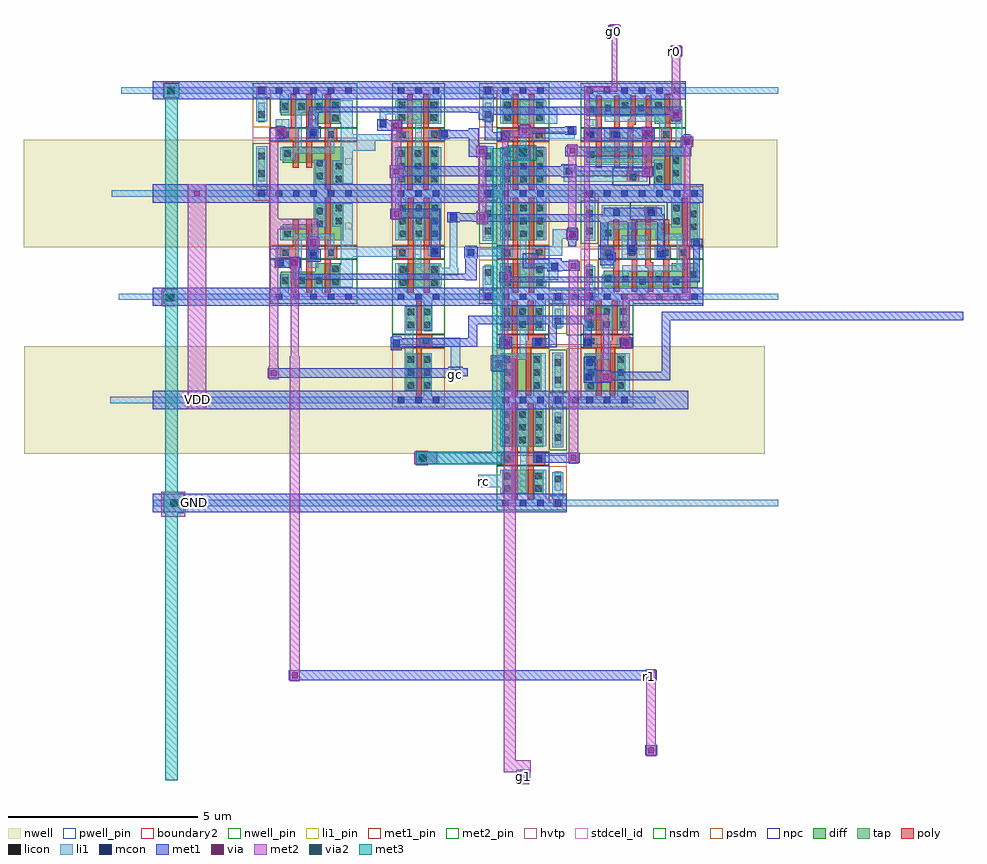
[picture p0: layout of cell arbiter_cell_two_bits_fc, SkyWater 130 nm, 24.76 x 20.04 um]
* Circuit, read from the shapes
.subckt arbiter_cell_two_bits_fc GND VDD g0 g1 gc r0 r1 rc
XM1 n1 r1 GND GND sky130_fd_pr__nfet_01v8 w=0.42 l=0.15
XM2 n2 gc GND GND sky130_fd_pr__nfet_01v8 w=0.42 l=0.15
XM3 GND gc n1 GND sky130_fd_pr__nfet_01v8 w=0.42 l=0.15
XM4 GND r0 n2 GND sky130_fd_pr__nfet_01v8 w=0.42 l=0.15
XM5 sky130_fd_sc_hd__nand2_1_8/B n1 GND GND sky130_fd_pr__nfet_01v8 w=0.65 l=0.15
XM6 sky130_fd_sc_hd__nand2_1_15/A n2 GND GND sky130_fd_pr__nfet_01v8 w=0.65 l=0.15
XM7 n3 sky130_fd_sc_hd__nand2_1_15/A sky130_fd_sc_hd__nand2_1_8/A GND sky130_fd_pr__nfet_01v8 w=0.65 l=0.15
XM8 n4 sky130_fd_sc_hd__nand2_1_8/B GND GND sky130_fd_pr__nfet_01v8 w=0.65 l=0.15
XM9 GND gc sky130_fd_sc_hd__nor2_1_3/A GND sky130_fd_pr__nfet_01v8 w=0.65 l=0.15
XM10 GND sky130_fd_sc_hd__or4_1_11/A n3 GND sky130_fd_pr__nfet_01v8 w=0.65 l=0.15
XM11 sky130_fd_sc_hd__or4_1_11/A sky130_fd_sc_hd__nand2_1_8/A n4 GND sky130_fd_pr__nfet_01v8 w=0.65 l=0.15
XM12 n5 sky130_fd_sc_hd__nand2_1_2/A rc GND sky130_fd_pr__nfet_01v8 w=0.65 l=0.15
XM13 g1 sky130_fd_sc_hd__nand2_1_17/A GND GND sky130_fd_pr__nfet_01v8 w=0.65 l=0.15
XM14 n6 r1 GND GND sky130_fd_pr__nfet_01v8 w=0.65 l=0.15
XM15 n7 r0 GND GND sky130_fd_pr__nfet_01v8 w=0.65 l=0.15
XM16 GND sky130_fd_sc_hd__nand2_1_2/B n5 GND sky130_fd_pr__nfet_01v8 w=0.65 l=0.15
XM17 GND sky130_fd_sc_hd__nor2_1_3/A g1 GND sky130_fd_pr__nfet_01v8 w=0.65 l=0.15
XM18 sky130_fd_sc_hd__nand2_1_2/B sky130_fd_sc_hd__nand2_1_10/A n6 GND sky130_fd_pr__nfet_01v8 w=0.65 l=0.15
XM19 sky130_fd_sc_hd__nand2_1_2/A sky130_fd_sc_hd__nand2_1_17/A n7 GND sky130_fd_pr__nfet_01v8 w=0.65 l=0.15
XM20 g0 sky130_fd_sc_hd__nor2_1_3/A GND GND sky130_fd_pr__nfet_01v8 w=0.65 l=0.15
XM21 n8 sky130_fd_sc_hd__nand2_1_8/A GND GND sky130_fd_pr__nfet_01v8 w=0.42 l=0.15 m=4
XM22 GND sky130_fd_sc_hd__nand2_1_10/A g0 GND sky130_fd_pr__nfet_01v8 w=0.65 l=0.15
XM23 n9 sky130_fd_sc_hd__or4_1_11/A GND GND sky130_fd_pr__nfet_01v8 w=0.42 l=0.15 m=4
XM24 sky130_fd_sc_hd__nand2_1_10/A n8 GND GND sky130_fd_pr__nfet_01v8 w=0.65 l=0.15
XM25 sky130_fd_sc_hd__nand2_1_17/A n9 GND GND sky130_fd_pr__nfet_01v8 w=0.65 l=0.15
XM26 n10 r1 n1 VDD sky130_fd_pr__pfet_01v8_hvt w=0.42 l=0.15
XM27 n11 gc n2 VDD sky130_fd_pr__pfet_01v8_hvt w=0.42 l=0.15
XM28 VDD gc n10 VDD sky130_fd_pr__pfet_01v8_hvt w=0.42 l=0.15
XM29 VDD r0 n11 VDD sky130_fd_pr__pfet_01v8_hvt w=0.42 l=0.15
XM30 sky130_fd_sc_hd__nand2_1_8/B n1 VDD VDD sky130_fd_pr__pfet_01v8_hvt w=1 l=0.15
XM31 sky130_fd_sc_hd__nand2_1_15/A n2 VDD VDD sky130_fd_pr__pfet_01v8_hvt w=1 l=0.15
XM32 sky130_fd_sc_hd__nand2_1_8/A sky130_fd_sc_hd__nand2_1_15/A VDD VDD sky130_fd_pr__pfet_01v8_hvt w=1 l=0.15
XM33 sky130_fd_sc_hd__or4_1_11/A sky130_fd_sc_hd__nand2_1_8/B VDD VDD sky130_fd_pr__pfet_01v8_hvt w=1 l=0.15
XM34 VDD gc sky130_fd_sc_hd__nor2_1_3/A VDD sky130_fd_pr__pfet_01v8_hvt w=1 l=0.15
XM35 VDD sky130_fd_sc_hd__or4_1_11/A sky130_fd_sc_hd__nand2_1_8/A VDD sky130_fd_pr__pfet_01v8_hvt w=1 l=0.15
XM36 VDD sky130_fd_sc_hd__nand2_1_8/A sky130_fd_sc_hd__or4_1_11/A VDD sky130_fd_pr__pfet_01v8_hvt w=1 l=0.15
XM37 rc sky130_fd_sc_hd__nand2_1_2/A VDD VDD sky130_fd_pr__pfet_01v8_hvt w=1 l=0.15
XM38 n12 sky130_fd_sc_hd__nand2_1_17/A g1 VDD sky130_fd_pr__pfet_01v8_hvt w=1 l=0.15
XM39 sky130_fd_sc_hd__nand2_1_2/B r1 VDD VDD sky130_fd_pr__pfet_01v8_hvt w=1 l=0.15
XM40 sky130_fd_sc_hd__nand2_1_2/A r0 VDD VDD sky130_fd_pr__pfet_01v8_hvt w=1 l=0.15
XM41 VDD sky130_fd_sc_hd__nor2_1_3/A n12 VDD sky130_fd_pr__pfet_01v8_hvt w=1 l=0.15
XM42 VDD sky130_fd_sc_hd__nand2_1_2/B rc VDD sky130_fd_pr__pfet_01v8_hvt w=1 l=0.15
XM43 VDD sky130_fd_sc_hd__nand2_1_10/A sky130_fd_sc_hd__nand2_1_2/B VDD sky130_fd_pr__pfet_01v8_hvt w=1 l=0.15
XM44 VDD sky130_fd_sc_hd__nand2_1_17/A sky130_fd_sc_hd__nand2_1_2/A VDD sky130_fd_pr__pfet_01v8_hvt w=1 l=0.15
XM45 n13 sky130_fd_sc_hd__nor2_1_3/A g0 VDD sky130_fd_pr__pfet_01v8_hvt w=1 l=0.15
XM46 n14 sky130_fd_sc_hd__nand2_1_8/A n8 VDD sky130_fd_pr__pfet_01v8_hvt w=0.42 l=0.15
XM47 VDD sky130_fd_sc_hd__nand2_1_10/A n13 VDD sky130_fd_pr__pfet_01v8_hvt w=1 l=0.15
XM48 n15 sky130_fd_sc_hd__or4_1_11/A n9 VDD sky130_fd_pr__pfet_01v8_hvt w=0.42 l=0.15
XM49 n16 sky130_fd_sc_hd__nand2_1_8/A n14 VDD sky130_fd_pr__pfet_01v8_hvt w=0.42 l=0.15
XM50 n17 sky130_fd_sc_hd__nand2_1_8/A n16 VDD sky130_fd_pr__pfet_01v8_hvt w=0.42 l=0.15
XM51 n18 sky130_fd_sc_hd__or4_1_11/A n15 VDD sky130_fd_pr__pfet_01v8_hvt w=0.42 l=0.15
XM52 n19 sky130_fd_sc_hd__or4_1_11/A n18 VDD sky130_fd_pr__pfet_01v8_hvt w=0.42 l=0.15
XM53 VDD sky130_fd_sc_hd__nand2_1_8/A n17 VDD sky130_fd_pr__pfet_01v8_hvt w=0.42 l=0.15
XM54 VDD sky130_fd_sc_hd__or4_1_11/A n19 VDD sky130_fd_pr__pfet_01v8_hvt w=0.42 l=0.15
XM55 sky130_fd_sc_hd__nand2_1_10/A n8 VDD VDD sky130_fd_pr__pfet_01v8_hvt w=1 l=0.15
XM56 sky130_fd_sc_hd__nand2_1_17/A n9 VDD VDD sky130_fd_pr__pfet_01v8_hvt w=1 l=0.15
.ends

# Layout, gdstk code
from math import pi, radians
import gdstk
lib = gdstk.Library(unit=1e-6, precision=1e-09)
def R(c, l, rs):  # rectangles x0, y0, x1, y1
    for r in rs: c.add(gdstk.rectangle(r[:2], r[2:], *l))
def A(c, l, x, y, w, h, nx, ny, dx, dy):  # array of equal rectangles
    R(c, l, [(x+i*dx, y+j*dy, x+i*dx+w, y+j*dy+h) for i in range(nx) for j in range(ny)])
def P(c, l, *ps):  # polygons
    for p in ps: c.add(gdstk.Polygon(p, *l))
nwell_pin = (64, 16)
nwell = (64, 20)
diff = (65, 20)
tap = (65, 44)
poly = (66, 20)
licon = (66, 44)
li1_pin = (67, 16)
li1 = (67, 20)
mcon = (67, 44)
met1_pin = (68, 16)
met1 = (68, 20)
via = (68, 44)
met2_pin = (69, 16)
met2 = (69, 20)
via2 = (69, 44)
met3 = (70, 20)
hvtp = (78, 44)
stdcell_id = (81, 4)
nsdm = (93, 44)
psdm = (94, 20)
npc = (95, 20)
pwell_pin = (122, 16)
boundary2 = (236, 0)

sky130_fd_sc_hd__inv_1 = lib.new_cell('sky130_fd_sc_hd__inv_1')
R(sky130_fd_sc_hd__inv_1, nwell_pin, [(0.145,2.635,0.315,2.805), (0.145,2.635,0.315,2.805)])
R(sky130_fd_sc_hd__inv_1, nwell, [(-0.19,1.305,1.57,2.91)])
R(sky130_fd_sc_hd__inv_1, diff, [(0.34,0.235,1.01,0.885), (0.34,1.485,1.01,2.485)])
P(sky130_fd_sc_hd__inv_1, poly, [(0.75,2.615),(0.6,2.615),(0.6,1.325),(0.32,1.325),(0.32,0.995),(0.6,0.995),(0.6,0.105),(0.75,0.105)])
A(sky130_fd_sc_hd__inv_1, licon, 0.38, 1.575, 0.17, 0.17, 1, 3, 0, 0.34)
A(sky130_fd_sc_hd__inv_1, licon, 0.8, 1.575, 0.17, 0.17, 1, 3, 0, 0.34)
R(sky130_fd_sc_hd__inv_1, licon, [(0.38,0.315,0.55,0.485), (0.8,0.315,0.97,0.485), (0.38,0.655,0.55,0.825), (0.8,0.655,0.97,0.825), (0.4,1.075,0.57,1.245)])
R(sky130_fd_sc_hd__inv_1, li1_pin, [(0.36,1.105,0.53,1.275), (0.82,1.105,0.99,1.275), (0.82,1.445,0.99,1.615)])
R(sky130_fd_sc_hd__inv_1, li1, [(0,-0.085,1.38,0.085), (0.32,0.005,0.55,0.905), (0.32,1.075,0.65,1.315), (0.34,1.495,0.55,2.675), (0,2.635,1.38,2.805)])
P(sky130_fd_sc_hd__inv_1, li1, [(1.05,2.465),(0.72,2.465),(0.72,1.485),(0.82,1.485),(0.82,0.885),(0.72,0.885),(0.72,0.255),(1.05,0.255)])
A(sky130_fd_sc_hd__inv_1, mcon, 0.145, -0.085, 0.17, 0.17, 3, 2, 0.46, 2.72)
R(sky130_fd_sc_hd__inv_1, met1_pin, [(0.145,-0.085,0.315,0.085), (0.145,-0.085,0.315,0.085), (0.145,2.635,0.315,2.805), (0.145,2.635,0.315,2.805)])
R(sky130_fd_sc_hd__inv_1, hvtp, [(0,1.25,1.38,2.72)])
R(sky130_fd_sc_hd__inv_1, stdcell_id, [(0,0,1.38,2.72)])
R(sky130_fd_sc_hd__inv_1, nsdm, [(0,-0.19,1.38,1.015)])
R(sky130_fd_sc_hd__inv_1, psdm, [(0,1.355,1.38,2.91)])
R(sky130_fd_sc_hd__inv_1, npc, [(0,0.975,1.38,1.345)])
R(sky130_fd_sc_hd__inv_1, pwell_pin, [(0.145,-0.085,0.315,0.085), (0.145,-0.085,0.315,0.085)])
R(sky130_fd_sc_hd__inv_1, boundary2, [(0,0,1.38,2.72)])
sky130_fd_sc_hd__inv_1.add(gdstk.FlexPath([(0,2.72),(1.38,2.72)], 0.48, ends="flush", simple_path=True, layer=68, datatype=20))  # met1
sky130_fd_sc_hd__inv_1.add(gdstk.FlexPath([(0,0),(1.38,0)], 0.48, ends="flush", simple_path=True, layer=68, datatype=20))  # met1
sky130_fd_sc_hd__inv_1.add(gdstk.Label('Y', (0.905,1.53), layer=67, texttype=5))
sky130_fd_sc_hd__inv_1.add(gdstk.Label('Y', (0.905,1.19), layer=67, texttype=5))
sky130_fd_sc_hd__inv_1.add(gdstk.Label('A', (0.445,1.19), layer=67, texttype=5))
sky130_fd_sc_hd__inv_1.add(gdstk.Label('VPB', (0.23,2.72), layer=64, texttype=5))
sky130_fd_sc_hd__inv_1.add(gdstk.Label('VNB', (0.23,0), layer=64, texttype=59))
sky130_fd_sc_hd__inv_1.add(gdstk.Label('VGND', (0.23,0), layer=68, texttype=5))
sky130_fd_sc_hd__inv_1.add(gdstk.Label('VPWR', (0.23,2.72), layer=68, texttype=5))
sky130_fd_sc_hd__inv_1.add(gdstk.Label('inv_1', (0,0), layer=83, texttype=44))

sky130_fd_sc_hd__fill_1 = lib.new_cell('sky130_fd_sc_hd__fill_1')
R(sky130_fd_sc_hd__fill_1, nwell_pin, [(0.155,2.67,0.255,2.755)])
R(sky130_fd_sc_hd__fill_1, nwell, [(-0.19,1.305,0.65,2.91)])
R(sky130_fd_sc_hd__fill_1, mcon, [(0.145,-0.085,0.315,0.085), (0.145,2.635,0.315,2.805)])
R(sky130_fd_sc_hd__fill_1, met1_pin, [(0.11,-0.065,0.29,0.08), (0.11,2.635,0.29,2.785)])
R(sky130_fd_sc_hd__fill_1, hvtp, [(0,1.25,0.46,2.72)])
R(sky130_fd_sc_hd__fill_1, stdcell_id, [(0,0,0.46,2.72)])
R(sky130_fd_sc_hd__fill_1, nsdm, [(0,-0.19,0.46,1.015)])
R(sky130_fd_sc_hd__fill_1, psdm, [(0,1.355,0.46,2.91)])
R(sky130_fd_sc_hd__fill_1, pwell_pin, [(0.14,-0.055,0.26,0.055)])
sky130_fd_sc_hd__fill_1.add(gdstk.FlexPath([(0,0),(0.46,0)], 0.17, ends="flush", simple_path=True, layer=67, datatype=20))  # li1
sky130_fd_sc_hd__fill_1.add(gdstk.FlexPath([(0,2.72),(0.46,2.72)], 0.17, ends="flush", simple_path=True, layer=67, datatype=20))  # li1
sky130_fd_sc_hd__fill_1.add(gdstk.FlexPath([(0,2.72),(0.46,2.72)], 0.48, ends="flush", simple_path=True, layer=68, datatype=20))  # met1
sky130_fd_sc_hd__fill_1.add(gdstk.FlexPath([(0,0),(0.46,0)], 0.48, ends="flush", simple_path=True, layer=68, datatype=20))  # met1
sky130_fd_sc_hd__fill_1.add(gdstk.Label('VPWR', (0.205,2.72), layer=68, texttype=5))
sky130_fd_sc_hd__fill_1.add(gdstk.Label('VGND', (0.205,0), layer=68, texttype=5))
sky130_fd_sc_hd__fill_1.add(gdstk.Label('VPB', (0.23,2.72), layer=64, texttype=5))
sky130_fd_sc_hd__fill_1.add(gdstk.Label('VNB', (0.23,0), layer=64, texttype=59))
sky130_fd_sc_hd__fill_1.add(gdstk.Label('fill_1', (0,0), layer=83, texttype=44))

sky130_fd_sc_hd__nand2_1 = lib.new_cell('sky130_fd_sc_hd__nand2_1')
R(sky130_fd_sc_hd__nand2_1, nwell_pin, [(0.14,2.635,0.31,2.805)])
R(sky130_fd_sc_hd__nand2_1, nwell, [(-0.19,1.305,1.57,2.91)])
R(sky130_fd_sc_hd__nand2_1, diff, [(0.155,0.235,1.245,0.885), (0.155,1.485,1.245,2.485)])
P(sky130_fd_sc_hd__nand2_1, poly, [(1.275,1.325),(0.985,1.325),(0.985,2.615),(0.835,2.615),(0.835,0.105),(0.985,0.105),(0.985,0.995),(1.275,0.995)],
  [(0.565,2.615),(0.415,2.615),(0.415,1.325),(0.105,1.325),(0.105,0.995),(0.415,0.995),(0.415,0.105),(0.565,0.105)])
A(sky130_fd_sc_hd__nand2_1, licon, 0.195, 1.575, 0.17, 0.17, 3, 3, 0.42, 0.34)
R(sky130_fd_sc_hd__nand2_1, licon, [(0.195,0.295,0.365,0.465), (1.035,0.295,1.205,0.465), (0.195,0.635,0.365,0.805), (1.035,0.635,1.205,0.805), (0.18,1.075,0.35,1.245), (1.02,1.075,1.19,1.245)])
A(sky130_fd_sc_hd__nand2_1, li1_pin, 0.14, 1.105, 0.17, 0.17, 3, 1, 0.46, 0)
R(sky130_fd_sc_hd__nand2_1, li1_pin, [(0.6,0.425,0.77,0.595), (0.6,0.765,0.77,0.935)])
R(sky130_fd_sc_hd__nand2_1, li1, [(0.095,1.055,0.43,1.325), (0.94,1.075,1.275,1.325)])
P(sky130_fd_sc_hd__nand2_1, li1, [(1.38,0.085),(0.395,0.085),(0.395,0.885),(0.085,0.885),(0.085,0.085),(0,0.085),(0,-0.085),(1.38,-0.085)],
  [(1.38,2.805),(0,2.805),(0,2.635),(0.085,2.635),(0.085,1.495),(0.365,1.495),(0.365,2.635),(1.035,2.635),(1.035,1.495),(1.295,1.495),(1.295,2.635),(1.38,2.635)],
  [(1.295,0.885),(0.77,0.885),(0.77,1.485),(0.865,1.485),(0.865,2.465),(0.535,2.465),(0.535,1.485),(0.6,1.485),(0.6,0.255),(1.295,0.255)])
A(sky130_fd_sc_hd__nand2_1, mcon, 0.145, -0.085, 0.17, 0.17, 3, 2, 0.46, 2.72)
R(sky130_fd_sc_hd__nand2_1, met1_pin, [(0.14,-0.085,0.31,0.085), (0.14,2.635,0.31,2.805)])
R(sky130_fd_sc_hd__nand2_1, hvtp, [(0,1.25,1.38,2.72)])
R(sky130_fd_sc_hd__nand2_1, stdcell_id, [(0,0,1.38,2.72)])
R(sky130_fd_sc_hd__nand2_1, nsdm, [(0,-0.19,1.38,1.015)])
R(sky130_fd_sc_hd__nand2_1, psdm, [(0,1.355,1.38,2.91)])
R(sky130_fd_sc_hd__nand2_1, npc, [(0,0.975,1.38,1.345)])
R(sky130_fd_sc_hd__nand2_1, pwell_pin, [(0.14,-0.085,0.31,0.085)])
R(sky130_fd_sc_hd__nand2_1, boundary2, [(0,0,1.38,2.72)])
sky130_fd_sc_hd__nand2_1.add(gdstk.FlexPath([(0,2.72),(1.38,2.72)], 0.48, ends="flush", simple_path=True, layer=68, datatype=20))  # met1
sky130_fd_sc_hd__nand2_1.add(gdstk.FlexPath([(0,0),(1.38,0)], 0.48, ends="flush", simple_path=True, layer=68, datatype=20))  # met1
sky130_fd_sc_hd__nand2_1.add(gdstk.Label('Y', (0.685,0.51), layer=67, texttype=5))
sky130_fd_sc_hd__nand2_1.add(gdstk.Label('Y', (0.685,0.85), layer=67, texttype=5))
sky130_fd_sc_hd__nand2_1.add(gdstk.Label('Y', (0.685,1.19), layer=67, texttype=5))
sky130_fd_sc_hd__nand2_1.add(gdstk.Label('B', (0.225,1.19), layer=67, texttype=5))
sky130_fd_sc_hd__nand2_1.add(gdstk.Label('A', (1.145,1.19), layer=67, texttype=5))
sky130_fd_sc_hd__nand2_1.add(gdstk.Label('VPB', (0.225,2.72), layer=64, texttype=5))
sky130_fd_sc_hd__nand2_1.add(gdstk.Label('VNB', (0.225,0), layer=64, texttype=59))
sky130_fd_sc_hd__nand2_1.add(gdstk.Label('VGND', (0.23,0), layer=68, texttype=5))
sky130_fd_sc_hd__nand2_1.add(gdstk.Label('VPWR', (0.225,2.72), layer=68, texttype=5))
sky130_fd_sc_hd__nand2_1.add(gdstk.Label('nand2_1', (0,0), layer=83, texttype=44))

sky130_fd_sc_hd__nor2_1 = lib.new_cell('sky130_fd_sc_hd__nor2_1')
R(sky130_fd_sc_hd__nor2_1, nwell_pin, [(0.15,2.635,0.32,2.805)])
R(sky130_fd_sc_hd__nor2_1, nwell, [(-0.19,1.305,1.57,2.91)])
R(sky130_fd_sc_hd__nor2_1, diff, [(0.135,0.235,1.225,0.885), (0.135,1.485,1.165,2.485)])
P(sky130_fd_sc_hd__nor2_1, poly, [(1.275,1.325),(0.905,1.325),(0.905,2.615),(0.755,2.615),(0.755,1.175),(0.815,1.175),(0.815,0.105),(0.965,0.105),(0.965,0.995),(1.275,0.995)],
  [(0.545,2.615),(0.395,2.615),(0.395,1.325),(0.11,1.325),(0.11,0.995),(0.395,0.995),(0.395,0.105),(0.545,0.105)])
A(sky130_fd_sc_hd__nor2_1, licon, 0.175, 0.305, 0.17, 0.17, 3, 2, 0.42, 0.34)
A(sky130_fd_sc_hd__nor2_1, licon, 0.175, 1.575, 0.17, 0.17, 1, 3, 0, 0.34)
A(sky130_fd_sc_hd__nor2_1, licon, 0.955, 1.575, 0.17, 0.17, 1, 3, 0, 0.34)
R(sky130_fd_sc_hd__nor2_1, licon, [(0.185,1.075,0.355,1.245), (1.025,1.075,1.195,1.245)])
R(sky130_fd_sc_hd__nor2_1, li1_pin, [(0.145,1.105,0.315,1.275), (1.065,1.105,1.235,1.275), (0.15,2.125,0.32,2.295)])
R(sky130_fd_sc_hd__nor2_1, li1, [(0.085,1.075,0.435,1.325), (0.945,1.075,1.295,1.325)])
P(sky130_fd_sc_hd__nor2_1, li1, [(1.38,0.085),(1.285,0.085),(1.285,0.895),(1.015,0.895),(1.015,0.085),(0.345,0.085),(0.345,0.895),(0.105,0.895),(0.105,0.085),(0,0.085),(0,-0.085),(1.38,-0.085)],
  [(1.38,2.805),(0,2.805),(0,2.635),(0.955,2.635),(0.955,1.495),(1.285,1.495),(1.285,2.635),(1.38,2.635)],
  [(0.845,0.895),(0.775,0.895),(0.775,1.665),(0.425,1.665),(0.425,2.45),(0.095,2.45),(0.095,1.495),(0.605,1.495),(0.605,0.895),(0.515,0.895),(0.515,0.255),(0.845,0.255)])
A(sky130_fd_sc_hd__nor2_1, mcon, 0.145, -0.085, 0.17, 0.17, 3, 2, 0.46, 2.72)
R(sky130_fd_sc_hd__nor2_1, met1_pin, [(0.15,-0.085,0.32,0.085), (0.15,2.635,0.32,2.805)])
R(sky130_fd_sc_hd__nor2_1, hvtp, [(0,1.25,1.38,2.72)])
R(sky130_fd_sc_hd__nor2_1, stdcell_id, [(0,0,1.38,2.72)])
R(sky130_fd_sc_hd__nor2_1, nsdm, [(0,-0.19,1.38,1.015)])
R(sky130_fd_sc_hd__nor2_1, psdm, [(0,1.355,1.38,2.91)])
R(sky130_fd_sc_hd__nor2_1, npc, [(0,0.975,1.38,1.345)])
R(sky130_fd_sc_hd__nor2_1, pwell_pin, [(0.15,-0.085,0.32,0.085)])
R(sky130_fd_sc_hd__nor2_1, boundary2, [(0,0,1.38,2.72)])
sky130_fd_sc_hd__nor2_1.add(gdstk.FlexPath([(0,2.72),(1.38,2.72)], 0.48, ends="flush", simple_path=True, layer=68, datatype=20))  # met1
sky130_fd_sc_hd__nor2_1.add(gdstk.FlexPath([(0,0),(1.38,0)], 0.48, ends="flush", simple_path=True, layer=68, datatype=20))  # met1
sky130_fd_sc_hd__nor2_1.add(gdstk.Label('B', (0.23,1.19), layer=67, texttype=5))
sky130_fd_sc_hd__nor2_1.add(gdstk.Label('Y', (0.235,2.21), layer=67, texttype=5))
sky130_fd_sc_hd__nor2_1.add(gdstk.Label('A', (1.15,1.19), layer=67, texttype=5))
sky130_fd_sc_hd__nor2_1.add(gdstk.Label('VPB', (0.235,2.72), layer=64, texttype=5))
sky130_fd_sc_hd__nor2_1.add(gdstk.Label('VNB', (0.235,0), layer=64, texttype=59))
sky130_fd_sc_hd__nor2_1.add(gdstk.Label('VGND', (0.23,0), layer=68, texttype=5))
sky130_fd_sc_hd__nor2_1.add(gdstk.Label('VPWR', (0.23,2.72), layer=68, texttype=5))
sky130_fd_sc_hd__nor2_1.add(gdstk.Label('nor2_1', (0,0), layer=83, texttype=44))

sky130_fd_sc_hd__tapvpwr = lib.new_cell('sky130_fd_sc_hd__tapvpwrvgnd_1')
R(sky130_fd_sc_hd__tapvpwr, nwell, [(-0.19,1.305,0.65,2.91)])
R(sky130_fd_sc_hd__tapvpwr, tap, [(0.145,0.32,0.315,0.845), (0.145,1.525,0.315,2.4)])
R(sky130_fd_sc_hd__tapvpwr, licon, [(0.145,0.555,0.315,0.725), (0.145,1.645,0.315,1.815), (0.145,2.11,0.315,2.28)])
R(sky130_fd_sc_hd__tapvpwr, li1, [(0,-0.085,0.46,0.085), (0.085,0,0.375,0.81), (0.085,1.47,0.375,2.72), (0,2.635,0.46,2.805)])
R(sky130_fd_sc_hd__tapvpwr, mcon, [(0.145,-0.085,0.315,0.085), (0.145,2.635,0.315,2.805)])
R(sky130_fd_sc_hd__tapvpwr, met1_pin, [(0.105,-0.09,0.36,0.1), (0.11,2.62,0.375,2.765)])
R(sky130_fd_sc_hd__tapvpwr, met1, [(0,-0.24,0.46,0.24), (0,2.48,0.46,2.96)])
R(sky130_fd_sc_hd__tapvpwr, hvtp, [(0,1.25,0.46,2.72)])
R(sky130_fd_sc_hd__tapvpwr, stdcell_id, [(0,0,0.46,2.72)])
R(sky130_fd_sc_hd__tapvpwr, nsdm, [(0,-0.19,0.46,0.19), (0,1.395,0.46,2.53)])
R(sky130_fd_sc_hd__tapvpwr, psdm, [(0,0.19,0.46,0.975), (0,2.53,0.46,2.91)])
sky130_fd_sc_hd__tapvpwr.add(gdstk.Label('VPWR', (0.23,2.72), layer=68, texttype=5))
sky130_fd_sc_hd__tapvpwr.add(gdstk.Label('VGND', (0.23,0), layer=68, texttype=5))
sky130_fd_sc_hd__tapvpwr.add(gdstk.Label('tapvpwrvgnd_1', (0,0), layer=83, texttype=44))

sky130_fd_sc_hd__or2_1 = lib.new_cell('sky130_fd_sc_hd__or2_1')
R(sky130_fd_sc_hd__or2_1, nwell_pin, [(0.145,2.635,0.315,2.805)])
R(sky130_fd_sc_hd__or2_1, nwell, [(-0.19,1.305,2.49,2.91)])
P(sky130_fd_sc_hd__or2_1, diff, [(1.855,0.885),(1.185,0.885),(1.185,0.655),(0.28,0.655),(0.28,0.235),(1.855,0.235)],
  [(1.935,2.485),(1.185,2.485),(1.185,1.905),(0.34,1.905),(0.34,1.485),(1.935,1.485)])
P(sky130_fd_sc_hd__or2_1, poly, [(0.75,2.035),(0.6,2.035),(0.6,1.325),(0.25,1.325),(0.25,0.995),(0.54,0.995),(0.54,0.105),(0.69,0.105),(0.69,0.995),(0.75,0.995)],
  [(1.775,1.325),(1.595,1.325),(1.595,2.615),(1.445,2.615),(1.445,0.105),(1.595,0.105),(1.595,0.995),(1.775,0.995)],
  [(1.23,1.325),(1.11,1.325),(1.11,2.035),(0.96,2.035),(0.96,0.105),(1.11,0.105),(1.11,0.995),(1.23,0.995)])
R(sky130_fd_sc_hd__or2_1, licon, [(1.645,0.305,1.815,0.475), (0.32,0.345,0.49,0.515), (0.74,0.345,0.91,0.515), (1.22,0.345,1.39,0.515), (1.645,0.645,1.815,0.815), (0.33,1.075,0.5,1.245), (1.01,1.075,1.18,1.245), (1.525,1.075,1.695,1.245), (0.38,1.575,0.55,1.745), (1.225,1.835,1.395,2.005), (1.725,1.915,1.895,2.085), (1.225,2.175,1.395,2.345), (1.725,2.255,1.895,2.425)])
R(sky130_fd_sc_hd__or2_1, li1_pin, [(0.145,0.765,0.315,0.935), (1.065,0.765,1.235,0.935), (0.145,1.105,0.315,1.275), (1.065,1.105,1.235,1.275), (1.985,1.785,2.155,1.955)])
R(sky130_fd_sc_hd__or2_1, li1, [(0.145,0.765,0.5,1.325), (1.01,0.765,1.275,1.325)])
P(sky130_fd_sc_hd__or2_1, li1, [(2.18,2.465),(1.645,2.465),(1.645,1.845),(1.865,1.845),(1.865,0.825),(1.565,0.825),(1.565,0.255),(2.18,0.255)],
  [(1.695,1.665),(0.66,1.665),(0.66,1.84),(0.27,1.84),(0.27,1.495),(0.67,1.495),(0.67,0.265),(0.95,0.265),(0.95,0.595),(0.84,0.595),(0.84,1.495),(1.525,1.495),(1.525,0.995),(1.695,0.995)],
  [(2.3,2.805),(0,2.805),(0,2.635),(1.145,2.635),(1.145,1.835),(1.475,1.835),(1.475,2.635),(2.3,2.635)],
  [(2.3,0.085),(1.395,0.085),(1.395,0.595),(1.18,0.595),(1.18,0.085),(0.49,0.085),(0.49,0.595),(0.25,0.595),(0.25,0.085),(0,0.085),(0,-0.085),(2.3,-0.085)])
A(sky130_fd_sc_hd__or2_1, mcon, 0.145, -0.085, 0.17, 0.17, 5, 2, 0.46, 2.72)
R(sky130_fd_sc_hd__or2_1, met1_pin, [(0.145,-0.085,0.315,0.085), (0.145,2.635,0.315,2.805)])
R(sky130_fd_sc_hd__or2_1, hvtp, [(0,1.25,2.3,2.72)])
R(sky130_fd_sc_hd__or2_1, stdcell_id, [(0,0,2.3,2.72)])
R(sky130_fd_sc_hd__or2_1, nsdm, [(0,-0.19,2.3,1.015)])
R(sky130_fd_sc_hd__or2_1, psdm, [(0,1.355,2.3,2.91)])
R(sky130_fd_sc_hd__or2_1, npc, [(0,0.975,2.3,1.345)])
R(sky130_fd_sc_hd__or2_1, pwell_pin, [(0.145,-0.085,0.315,0.085)])
R(sky130_fd_sc_hd__or2_1, boundary2, [(0,0,2.3,2.72)])
sky130_fd_sc_hd__or2_1.add(gdstk.FlexPath([(0,2.72),(2.3,2.72)], 0.48, ends="flush", simple_path=True, layer=68, datatype=20))  # met1
sky130_fd_sc_hd__or2_1.add(gdstk.FlexPath([(0,0),(2.3,0)], 0.48, ends="flush", simple_path=True, layer=68, datatype=20))  # met1
sky130_fd_sc_hd__or2_1.add(gdstk.Label('A', (1.15,1.19), layer=67, texttype=5))
sky130_fd_sc_hd__or2_1.add(gdstk.Label('X', (2.07,1.87), layer=67, texttype=5))
sky130_fd_sc_hd__or2_1.add(gdstk.Label('B', (0.23,1.19), layer=67, texttype=5))
sky130_fd_sc_hd__or2_1.add(gdstk.Label('VPB', (0.23,2.72), layer=64, texttype=5))
sky130_fd_sc_hd__or2_1.add(gdstk.Label('VNB', (0.23,0), layer=64, texttype=59))
sky130_fd_sc_hd__or2_1.add(gdstk.Label('VGND', (0.23,0), layer=68, texttype=5))
sky130_fd_sc_hd__or2_1.add(gdstk.Label('VPWR', (0.23,2.72), layer=68, texttype=5))
sky130_fd_sc_hd__or2_1.add(gdstk.Label('or2_1', (0,0), layer=83, texttype=44))

sky130_fd_sc_hd__or4_1 = lib.new_cell('sky130_fd_sc_hd__or4_1')
R(sky130_fd_sc_hd__or4_1, nwell_pin, [(0.15,2.635,0.32,2.805)])
R(sky130_fd_sc_hd__or4_1, nwell, [(-0.19,1.305,2.95,2.91)])
P(sky130_fd_sc_hd__or4_1, diff, [(2.625,0.885),(1.94,0.885),(1.94,0.685),(0.135,0.685),(0.135,0.265),(1.94,0.265),(1.94,0.235),(2.625,0.235)],
  [(2.625,2.485),(1.94,2.485),(1.94,1.905),(0.135,1.905),(0.135,1.485),(2.625,1.485)])
P(sky130_fd_sc_hd__or4_1, poly, [(2.39,1.325),(2.355,1.325),(2.355,2.615),(2.205,2.615),(2.205,1.325),(2.115,1.325),(2.115,0.995),(2.205,0.995),(2.205,0.105),(2.355,0.105),(2.355,0.995),(2.39,0.995)],
  [(1.905,1.325),(1.865,1.325),(1.865,2.035),(1.715,2.035),(1.715,1.325),(1.635,1.325),(1.635,0.995),(1.715,0.995),(1.715,0.135),(1.865,0.135),(1.865,0.995),(1.905,0.995)],
  [(1.535,2.415),(1.205,2.415),(1.205,2.145),(1.235,2.145),(1.235,0.76),(1.295,0.76),(1.295,0.135),(1.445,0.135),(1.445,0.905),(1.44,0.905),(1.44,0.91),(1.385,0.91),(1.385,2.145),(1.535,2.145)],
  [(1.025,2.035),(0.875,2.035),(0.875,1.325),(0.755,1.325),(0.755,0.995),(0.875,0.995),(0.875,0.135),(1.025,0.135)],
  [(0.545,2.035),(0.395,2.035),(0.395,1.325),(0.125,1.325),(0.125,0.995),(0.395,0.995),(0.395,0.135),(0.545,0.135)])
R(sky130_fd_sc_hd__or4_1, licon, [(1.075,0.315,1.245,0.485), (1.965,0.315,2.135,0.485), (0.625,0.385,0.795,0.555), (1.495,0.385,1.665,0.555), (0.175,0.415,0.345,0.585), (2.405,0.505,2.575,0.675), (0.175,1.075,0.345,1.245), (0.805,1.075,0.975,1.245), (1.685,1.075,1.855,1.245), (2.165,1.075,2.335,1.245), (0.175,1.6,0.345,1.77), (2.405,1.76,2.575,1.93), (1.98,1.915,2.15,2.085), (2.405,2.1,2.575,2.27), (1.285,2.195,1.455,2.365), (1.98,2.255,2.15,2.425)])
A(sky130_fd_sc_hd__or4_1, li1_pin, 0.15, 1.105, 0.17, 0.17, 4, 1, 0.46, 0)
A(sky130_fd_sc_hd__or4_1, li1_pin, 0.15, 2.125, 0.17, 0.17, 3, 1, 0.46, 0)
R(sky130_fd_sc_hd__or4_1, li1_pin, [(0.15,0.765,0.32,0.935), (0.61,1.445,0.78,1.615), (1.07,1.445,1.24,1.615), (2.45,1.785,2.62,1.955)])
R(sky130_fd_sc_hd__or4_1, li1, [(0.09,0.755,0.44,1.325), (0.61,0.995,1.32,1.615), (1.49,0.995,1.895,1.325), (0.09,2.125,1.745,2.415)])
P(sky130_fd_sc_hd__or4_1, li1, [(2.76,0.085),(2.215,0.085),(2.215,0.485),(1.835,0.485),(1.835,0.085),(1.325,0.085),(1.325,0.485),(0.995,0.485),(0.995,0.085),(0.425,0.085),(0.425,0.585),(0.095,0.585),(0.095,0.085),(0,0.085),(0,-0.085),(2.76,-0.085)],
  [(2.76,2.805),(0,2.805),(0,2.635),(1.915,2.635),(1.915,1.835),(2.195,1.835),(2.195,2.635),(2.76,2.635)],
  [(2.675,2.465),(2.405,2.465),(2.405,1.495),(2.505,1.495),(2.505,0.76),(2.405,0.76),(2.405,0.415),(2.675,0.415)],
  [(2.335,1.325),(2.235,1.325),(2.235,1.665),(1.68,1.665),(1.68,1.955),(0.09,1.955),(0.09,1.495),(0.41,1.495),(0.41,1.785),(1.51,1.785),(1.51,1.495),(2.065,1.495),(2.065,0.825),(0.625,0.825),(0.625,0.305),(0.795,0.305),(0.795,0.655),(1.495,0.655),(1.495,0.305),(1.665,0.305),(1.665,0.655),(2.235,0.655),(2.235,0.995),(2.335,0.995)])
A(sky130_fd_sc_hd__or4_1, mcon, 0.145, -0.085, 0.17, 0.17, 6, 2, 0.46, 2.72)
R(sky130_fd_sc_hd__or4_1, met1_pin, [(0.15,-0.085,0.32,0.085), (0.15,2.635,0.32,2.805)])
R(sky130_fd_sc_hd__or4_1, hvtp, [(0,1.25,2.76,2.72)])
R(sky130_fd_sc_hd__or4_1, stdcell_id, [(0,0,2.76,2.72)])
R(sky130_fd_sc_hd__or4_1, nsdm, [(0,-0.19,2.76,1.015)])
P(sky130_fd_sc_hd__or4_1, psdm, [(2.76,2.91),(1.81,2.91),(1.81,2.035),(0.845,2.035),(0.845,2.495),(1.81,2.495),(1.81,2.91),(0,2.91),(0,1.355),(2.76,1.355)])
R(sky130_fd_sc_hd__or4_1, npc, [(0,0.975,2.76,1.345), (0.845,2.035,1.81,2.495)])
R(sky130_fd_sc_hd__or4_1, pwell_pin, [(0.15,-0.085,0.32,0.085)])
R(sky130_fd_sc_hd__or4_1, boundary2, [(0,0,2.76,2.72)])
sky130_fd_sc_hd__or4_1.add(gdstk.FlexPath([(0,2.72),(2.76,2.72)], 0.48, ends="flush", simple_path=True, layer=68, datatype=20))  # met1
sky130_fd_sc_hd__or4_1.add(gdstk.FlexPath([(0,0),(2.76,0)], 0.48, ends="flush", simple_path=True, layer=68, datatype=20))  # met1
sky130_fd_sc_hd__or4_1.add(gdstk.Label('C', (1.155,1.19), layer=67, texttype=5))
sky130_fd_sc_hd__or4_1.add(gdstk.Label('A', (1.615,1.19), layer=67, texttype=5))
sky130_fd_sc_hd__or4_1.add(gdstk.Label('X', (2.535,1.87), layer=67, texttype=5))
sky130_fd_sc_hd__or4_1.add(gdstk.Label('C', (0.695,1.19), layer=67, texttype=5))
sky130_fd_sc_hd__or4_1.add(gdstk.Label('B', (1.155,2.21), layer=67, texttype=5))
sky130_fd_sc_hd__or4_1.add(gdstk.Label('B', (0.695,2.21), layer=67, texttype=5))
sky130_fd_sc_hd__or4_1.add(gdstk.Label('C', (0.695,1.53), layer=67, texttype=5))
sky130_fd_sc_hd__or4_1.add(gdstk.Label('B', (0.235,2.21), layer=67, texttype=5))
sky130_fd_sc_hd__or4_1.add(gdstk.Label('C', (1.155,1.53), layer=67, texttype=5))
sky130_fd_sc_hd__or4_1.add(gdstk.Label('D', (0.235,1.19), layer=67, texttype=5))
sky130_fd_sc_hd__or4_1.add(gdstk.Label('D', (0.235,0.85), layer=67, texttype=5))
sky130_fd_sc_hd__or4_1.add(gdstk.Label('VPWR', (0.235,2.72), layer=68, texttype=5))
sky130_fd_sc_hd__or4_1.add(gdstk.Label('VGND', (0.235,0), layer=68, texttype=5))
sky130_fd_sc_hd__or4_1.add(gdstk.Label('VPB', (0.235,2.72), layer=64, texttype=5))
sky130_fd_sc_hd__or4_1.add(gdstk.Label('VNB', (0.235,0), layer=64, texttype=59))
sky130_fd_sc_hd__or4_1.add(gdstk.Label('or4_1', (0,0), layer=83, texttype=44))

arbiter_cell_two_bits_fc = lib.new_cell('arbiter_cell_two_bits_fc')
R(arbiter_cell_two_bits_fc, nwell, [(4.925,22.48,18.285,22.57), (18.37,22.48,24.44,22.505), (18.37,22.505,18.415,22.57), (18.85,22.505,24.44,22.66), (4.925,22.57,18.415,22.66), (4.925,22.66,24.44,25.31), (4.915,27.915,24.78,30.715), (4.915,30.715,18.325,30.755), (18.74,30.715,24.78,30.75)])
R(arbiter_cell_two_bits_fc, li1_pin, [(17.02,21.715,17.055,21.75)])
R(arbiter_cell_two_bits_fc, li1, [(8.33,21.09,24.8,21.26), (16.89,21.59,17.53,21.64), (16.89,21.64,17.64,21.81), (16.89,21.81,17.53,21.92), (15.255,22.2,16.585,22.235), (15.255,22.235,17.785,22.5), (18.37,22.245,18.675,22.495), (15.255,22.5,16.585,22.53), (7.195,23.81,21.565,23.98), (19.73,24.42,19.9,24.8), (16.17,24.48,16.415,25.295), (17.28,24.7,17.7,24.87), (19.73,24.8,19.91,24.97), (17.28,24.87,17.59,25.02), (19.73,24.97,19.9,25.035), (14.62,25.265,15.185,25.495), (15.37,25.295,16.415,25.54), (20.69,25.305,20.89,25.505), (18.38,25.32,18.55,25.49), (17.54,25.325,17.71,25.495), (19.69,25.325,19.86,25.495), (7.42,26.53,24.8,26.7), (15.225,26.95,15.925,27.18), (17.985,27.065,19.005,27.5), (15.225,27.18,16.37,27.385), (16.14,27.385,16.345,28.81), (11.59,27.425,11.76,27.595), (12.415,27.425,12.68,27.835), (18.835,27.5,19.005,27.505), (20.285,27.575,20.455,27.745), (16.58,27.66,16.82,27.68), (21.63,27.66,21.8,27.83), (13.485,27.675,15.055,27.935), (16.58,27.68,17.675,27.9), (18.4,27.695,19.105,27.94), (15.665,27.73,15.86,27.925), (20.84,27.79,21.35,27.995), (16.71,27.9,17.675,27.915), (17.48,27.915,17.675,27.925), (18.86,27.94,19.105,28.15), (22.565,27.94,22.735,28.11), (18.86,28.15,19.5,28.395), (20.45,28.755,20.62,28.925), (21.37,28.755,21.54,28.925), (7.235,29.25,20.475,29.42), (19.145,29.64,19.98,29.93), (19.145,29.93,19.435,30.08), (17.955,30.31,18.195,30.55), (13.27,30.47,14.18,30.73), (22.105,30.62,22.53,30.79), (13.27,30.73,15.065,30.785), (15.785,30.73,16.02,30.815), (20.37,30.745,21.44,31), (17.48,30.765,17.65,30.935), (18.44,30.775,19.435,30.97), (13.535,30.785,15.065,30.88), (19.74,30.79,19.935,30.985), (15.785,30.815,16.085,30.985), (12.415,30.82,12.68,31.245), (11.58,30.845,11.78,31.045), (13.58,30.88,14.79,30.905), (14.915,30.88,15.055,30.89), (19.25,30.97,19.42,31.085), (15.785,30.985,16.02,31), (14.295,31.075,14.465,31.42), (17.985,31.17,18.975,31.605), (14.295,31.42,15.015,31.59), (7.485,31.965,12.8,31.975), (19.745,31.965,24.8,31.97), (13.545,31.97,24.8,31.975), (7.485,31.975,24.8,32.14)])
R(arbiter_cell_two_bits_fc, mcon, [(15.335,22.28,15.505,22.45), (18.41,22.28,18.58,22.45), (19.73,24.42,19.9,24.59), (16.205,24.515,16.375,24.685), (17.35,24.77,17.52,24.94), (19.74,24.8,19.91,24.97), (14.65,25.295,14.82,25.465), (18.38,25.32,18.55,25.49), (20.705,25.32,20.875,25.49), (17.54,25.325,17.71,25.495), (19.69,25.325,19.86,25.495), (18.82,27.325,18.99,27.495), (11.59,27.425,11.76,27.595), (20.285,27.575,20.455,27.745), (12.46,27.615,12.63,27.785), (21.63,27.66,21.8,27.83), (16.615,27.695,16.785,27.865), (15.675,27.74,15.845,27.91), (20.855,27.805,21.025,27.975), (22.565,27.94,22.735,28.11), (19.29,28.185,19.46,28.355), (16.155,28.62,16.325,28.79), (20.45,28.755,20.62,28.925), (21.37,28.755,21.54,28.925), (19.205,29.85,19.375,30.02), (17.99,30.345,18.16,30.515), (22.31,30.62,22.48,30.79), (17.48,30.765,17.65,30.935), (21.225,30.785,21.395,30.955), (19.75,30.8,19.92,30.97), (20.47,30.8,20.64,30.97), (15.915,30.815,16.085,30.985), (11.595,30.86,11.765,31.03), (12.46,30.865,12.63,31.035), (19.25,30.915,19.42,31.085), (14.295,31.1,14.465,31.27)])
R(arbiter_cell_two_bits_fc, met1_pin, [(9.29,21.195,9.51,21.21), (16.26,24.535,16.34,24.615)])
R(arbiter_cell_two_bits_fc, met1, [(17.9,13.8,18.27,14.14), (21.29,14.53,21.61,14.79), (11.9,16.505,12.22,16.51), (11.9,16.51,21.605,16.765), (21.285,16.765,21.605,16.77), (8.315,20.935,17.61,21.09), (8.315,21.09,17.435,21.11), (8.315,21.11,17.53,21.255), (8.315,21.255,17.505,21.26), (8.315,21.26,17.54,21.415), (15.24,22.17,15.57,22.2), (15.225,22.2,15.815,22.53), (18.35,22.235,18.775,22.245), (19.245,22.24,19.565,22.245), (18.35,22.245,19.565,22.495), (18.35,22.495,18.775,22.505), (19.245,22.495,19.565,22.5), (15.24,22.53,15.57,22.56), (8.315,23.655,22.435,24.135), (20.125,24.345,20.385,24.35), (19.67,24.35,20.405,24.415), (19.67,24.415,21.95,24.64), (16.1,24.44,16.49,24.48), (11.34,24.475,11.66,24.48), (11.34,24.48,16.49,24.525), (11.34,24.525,16.615,24.725), (17.25,24.64,17.62,24.67), (19.67,24.64,20.405,24.675), (21.725,24.64,21.95,26), (17.22,24.67,17.65,25.075), (19.67,24.675,19.98,25.03), (11.34,24.725,11.66,24.735), (16.1,24.725,16.615,24.73), (16.1,24.73,16.49,24.765), (14.59,25.205,14.88,25.295), (17.445,25.255,17.765,25.27), (19.66,25.265,19.89,25.885), (17.445,25.27,17.77,25.515), (20.63,25.275,20.95,25.535), (18.32,25.29,18.965,25.52), (14.59,25.295,16.865,25.525), (17.465,25.515,17.77,25.56), (18.735,25.52,18.965,25.885), (14.59,25.525,14.88,25.555), (16.635,25.525,16.865,25.885), (14.62,25.555,14.85,25.57), (16.625,25.885,19.89,26.115), (21.725,26,29.675,26.225), (8.315,26.375,22.425,26.855), (17.735,26.995,22.735,27), (17.445,27,22.735,27.145), (16.555,27.045,16.855,27.06), (12.005,27.06,16.855,27.225), (17.445,27.145,17.77,27.165), (22.56,27.145,22.735,27.165), (17.445,27.165,17.765,27.26), (22.565,27.165,22.735,27.91), (12.005,27.225,12.17,27.375), (16.555,27.225,16.855,27.6), (18.715,27.29,19.1,27.3), (19.245,27.295,19.565,27.3), (18.715,27.3,19.565,27.37), (18.07,27.36,18.475,27.37), (18.07,27.37,19.565,27.55), (11.54,27.375,12.17,27.38), (11.54,27.38,12.215,27.395), (11.53,27.395,12.215,27.625), (20.115,27.44,20.47,27.545), (12.355,27.54,12.74,27.865), (20.115,27.545,20.515,27.775), (18.07,27.55,19.1,27.63), (19.245,27.55,19.565,27.555), (16.55,27.6,16.855,27.63), (21.6,27.6,21.83,27.89), (11.54,27.625,12.215,27.64), (16.52,27.63,16.88,27.93), (18.07,27.63,18.475,27.765), (11.54,27.64,12.16,27.645), (15.635,27.67,15.89,28.68), (20.825,27.745,21.055,28.035), (20.115,27.775,20.47,27.935), (12.415,27.865,12.68,28.215), (21.61,27.89,21.815,28.59), (22.505,27.91,22.795,28.14), (16.55,27.93,16.85,27.96), (20.115,27.935,20.32,28.59), (19.27,27.94,19.48,28.09), (20.835,28.035,21.04,28.59), (19.245,28.09,19.505,28.105), (19.24,28.105,19.51,28.435), (16.08,28.575,16.405,28.605), (16.835,28.58,17.155,28.59), (16.735,28.59,21.815,28.605), (16.08,28.605,21.815,28.795), (14.575,28.675,14.895,28.68), (14.575,28.68,15.89,28.935), (16.08,28.795,17.155,28.81), (20.2,28.795,21.725,28.955), (16.08,28.81,16.405,28.84), (16.835,28.81,17.155,28.84), (8.315,29.095,22.355,29.575), (14.57,29.755,14.9,29.795), (19.085,29.76,19.495,29.795), (14.57,29.795,21.505,30.05), (14.57,30.05,14.9,30.08), (19.085,30.05,19.495,30.11), (21.185,30.05,21.505,30.055), (17.895,30.24,18.26,30.615), (16.645,30.31,17.135,30.57), (22.31,30.315,22.48,30.32), (19.185,30.32,22.51,30.545), (19.185,30.545,22.525,30.565), (19.215,30.565,19.535,30.6), (22.265,30.565,22.525,30.865), (16.645,30.57,16.905,30.795), (19.755,30.715,21.545,30.76), (17.42,30.735,17.71,30.74), (17.06,30.74,17.71,30.955), (19.68,30.76,21.545,31.015), (11.55,30.785,11.81,31.105), (15.855,30.785,16.145,30.795), (12.355,30.79,12.74,31.115), (15.855,30.795,16.905,31), (22.31,30.865,22.48,30.905), (17.955,30.87,18.275,30.915), (19.19,30.885,19.48,30.915), (17.955,30.915,19.48,31.085), (17.06,30.955,17.275,31.28), (17.42,30.955,17.71,30.965), (14.235,30.995,14.89,31.1), (15.855,31,16.145,31.015), (16.645,31,16.905,31.055), (19.755,31.015,21.545,31.06), (21.19,31.06,21.51,31.065), (17.955,31.085,18.275,31.13), (19.19,31.085,19.48,31.115), (14.235,31.1,14.895,31.27), (12.415,31.115,12.68,31.415), (21.975,31.245,22.235,31.415), (14.235,31.27,14.525,31.3), (16.905,31.28,17.275,31.415), (12.415,31.415,12.685,31.48), (16.905,31.415,22.235,31.47), (16.655,31.47,22.235,31.48), (12.415,31.48,22.235,31.515), (12.44,31.515,22.235,31.565), (12.44,31.565,22.21,31.63), (8.315,31.815,22.36,32.295), (21.95,32.96,22.27,33.22), (20.325,33.515,20.645,33.775)])
R(arbiter_cell_two_bits_fc, via, [(18.01,13.88,18.16,14.03), (21.375,14.585,21.525,14.735), (11.985,16.56,12.135,16.71), (21.37,16.565,21.52,16.715), (8.795,21.1,8.945,21.25), (15.33,22.29,15.48,22.44), (19.33,22.295,19.48,22.445), (9.405,23.825,9.555,23.975), (20.18,24.43,20.33,24.58), (11.425,24.53,11.575,24.68), (17.36,24.75,17.51,24.9), (17.53,25.31,17.68,25.46), (20.715,25.33,20.865,25.48), (8.735,26.515,8.885,26.665), (17.53,27.055,17.68,27.205), (19.33,27.35,19.48,27.5), (11.98,27.435,12.13,27.585), (12.47,27.975,12.62,28.125), (19.3,28.175,19.45,28.325), (16.92,28.635,17.07,28.785), (14.66,28.73,14.81,28.88), (9.4,29.26,9.55,29.41), (14.66,29.845,14.81,29.995), (21.27,29.85,21.42,30), (18,30.355,18.15,30.505), (16.9,30.365,17.05,30.515), (19.3,30.395,19.45,30.545), (22.32,30.63,22.47,30.78), (21.275,30.86,21.425,31.01), (11.605,30.87,11.755,31.02), (18.04,30.925,18.19,31.075), (14.655,31.05,14.805,31.2), (22.03,31.33,22.18,31.48), (8.725,31.98,8.875,32.13), (22.035,33.015,22.185,33.165), (20.41,33.57,20.56,33.72)])
R(arbiter_cell_two_bits_fc, met2_pin, [(18.035,13.91,18.115,14.01), (21.39,16.585,21.43,16.645), (9.325,23.76,9.635,24.045), (22.035,33.035,22.09,33.12), (20.425,33.595,20.485,33.635)])
R(arbiter_cell_two_bits_fc, met2, [(17.93,13.77,18.24,14.08), (17.57,14.08,18.275,14.39), (17.57,14.39,17.88,24.67), (21.32,14.5,21.58,14.82), (21.32,14.82,21.575,16.48), (11.93,16.475,12.19,16.795), (21.315,16.48,21.575,16.8), (11.93,16.795,12.185,25.05), (8.535,20.82,9.165,21.475), (15.29,22.18,15.57,22.2), (15.21,22.2,15.81,22.53), (19.275,22.21,19.535,22.53), (15.29,22.53,15.57,22.55), (19.28,22.53,19.53,27.265), (9.24,23.655,9.72,29.575), (20.095,24.375,20.415,24.635), (11.37,24.445,11.63,24.765), (20.18,24.635,20.33,26), (17.22,24.67,17.88,24.98), (11.38,24.765,11.625,28.4), (17.22,24.98,17.65,25.075), (11.95,25.05,12.16,27.35), (17.475,25.225,17.735,25.545), (20.66,25.245,20.92,25.565), (17.52,25.545,17.69,26.97), (20.705,25.565,20.875,26.525), (19.685,26,20.33,26.15), (19.685,26.15,19.835,32.015), (8.545,26.365,8.89,26.38), (8.545,26.38,8.97,26.83), (20.705,26.525,22.48,26.695), (22.31,26.695,22.48,30.575), (17.475,26.97,17.735,27.29), (19.275,27.265,19.535,27.585), (17.52,27.29,17.69,30.815), (11.925,27.35,12.185,27.67), (12.385,27.92,12.71,28.185), (19.215,28.12,19.535,28.38), (12.415,28.185,12.68,28.4), (19.27,28.38,19.48,30.31), (11.38,28.4,12.68,28.665), (16.85,28.53,17.145,28.885), (14.605,28.645,14.865,28.965), (11.38,28.665,11.625,30.815), (16.895,28.885,17.1,30.28), (14.605,28.965,14.86,29.745), (14.56,29.745,14.92,30.075), (21.215,29.765,21.475,30.085), (14.57,30.075,14.9,30.08), (14.605,30.08,14.86,30.965), (21.22,30.085,21.475,30.775), (17.895,30.24,18.26,30.615), (16.845,30.28,17.105,30.6), (19.245,30.31,19.505,30.63), (22.235,30.575,22.555,30.835), (21.22,30.775,21.48,31.095), (11.38,30.815,11.84,31.065), (17.52,30.815,18.325,30.985), (14.6,30.965,14.86,31.285), (17.985,30.985,18.245,31.16), (11.52,31.065,11.84,31.075), (21.945,31.275,22.265,31.535), (22,31.535,22.215,32.93), (8.585,31.855,9.015,32.26), (19.685,32.015,20.56,32.165), (20.41,32.165,20.56,33.485), (21.98,32.93,22.24,33.25), (20.355,33.485,20.615,33.805)])
R(arbiter_cell_two_bits_fc, via2, [(8.77,21.075,8.97,21.275), (15.33,22.265,15.53,22.465), (8.66,26.5,8.86,26.7), (17.975,30.33,18.175,30.53), (8.695,31.955,8.895,32.155)])
R(arbiter_cell_two_bits_fc, met3, [(8.645,13.87,8.975,20.91), (8.605,20.91,9.135,21.44), (8.645,21.44,8.975,26.425), (15.265,22.2,17.59,22.53), (17.26,22.53,17.59,30.2), (8.585,26.425,8.975,26.775), (8.645,26.775,8.975,31.855), (17.26,30.2,18.425,30.53), (17.68,30.53,18.42,30.615), (8.6,31.855,9.015,32.245)])
R(arbiter_cell_two_bits_fc, hvtp, [(17.6,23.84,18.47,23.95), (21.92,28.7,22.085,29.28), (12.67,29.28,13.18,29.39), (14.86,29.28,15.77,29.39), (17.62,29.28,18.55,29.39), (21.92,29.28,22.3,29.39), (22.135,29.39,22.3,29.705)])
R(arbiter_cell_two_bits_fc, nsdm, [(14.87,26.505,15.79,26.725), (17.415,26.505,18.735,26.725), (20.07,26.505,20.95,26.755)])
R(arbiter_cell_two_bits_fc, psdm, [(17.395,23.785,18.675,24.005), (12.465,29.225,13.465,29.445), (14.655,29.225,15.975,29.445), (17.415,29.225,18.755,29.445), (21.875,29.225,22.35,29.445)])
arbiter_cell_two_bits_fc.add(gdstk.Reference(sky130_fd_sc_hd__inv_1, (16.005,26.615), rotation=pi))
arbiter_cell_two_bits_fc.add(gdstk.Reference(sky130_fd_sc_hd__fill_1, (19.225,26.615), x_reflection=True))
arbiter_cell_two_bits_fc.add(gdstk.Reference(sky130_fd_sc_hd__nand2_1, (18.765,21.175), rotation=pi, x_reflection=True))
arbiter_cell_two_bits_fc.add(gdstk.Reference(sky130_fd_sc_hd__nor2_1, (17.385,26.615), x_reflection=True))
arbiter_cell_two_bits_fc.add(gdstk.Reference(sky130_fd_sc_hd__nor2_1, (19.6,26.615), x_reflection=True))
arbiter_cell_two_bits_fc.add(gdstk.Reference(sky130_fd_sc_hd__tapvpwr, (18.765,21.175)))
arbiter_cell_two_bits_fc.add(gdstk.Reference(sky130_fd_sc_hd__tapvpwr, (18.765,26.615), x_reflection=True))
arbiter_cell_two_bits_fc.add(gdstk.Reference(sky130_fd_sc_hd__or2_1, (11.405,26.615)))
arbiter_cell_two_bits_fc.add(gdstk.Reference(sky130_fd_sc_hd__nand2_1, (14.625,26.615)))
arbiter_cell_two_bits_fc.add(gdstk.Reference(sky130_fd_sc_hd__tapvpwr, (16.925,26.615)))
arbiter_cell_two_bits_fc.add(gdstk.Reference(sky130_fd_sc_hd__nand2_1, (17.385,26.615)))
arbiter_cell_two_bits_fc.add(gdstk.Reference(sky130_fd_sc_hd__or4_1, (20.06,26.615)))
arbiter_cell_two_bits_fc.add(gdstk.Reference(sky130_fd_sc_hd__tapvpwr, (19.6,26.615)))
arbiter_cell_two_bits_fc.add(gdstk.Reference(sky130_fd_sc_hd__or2_1, (11.405,32.055), x_reflection=True))
arbiter_cell_two_bits_fc.add(gdstk.Reference(sky130_fd_sc_hd__tapvpwr, (10.95,32.055), x_reflection=True))
arbiter_cell_two_bits_fc.add(gdstk.Reference(sky130_fd_sc_hd__nand2_1, (16.005,32.055), rotation=pi))
arbiter_cell_two_bits_fc.add(gdstk.Reference(sky130_fd_sc_hd__tapvpwr, (16.925,32.055), x_reflection=True))
arbiter_cell_two_bits_fc.add(gdstk.Reference(sky130_fd_sc_hd__nand2_1, (17.385,32.055), x_reflection=True))
arbiter_cell_two_bits_fc.add(gdstk.Reference(sky130_fd_sc_hd__or4_1, (19.6,32.055), x_reflection=True))
arbiter_cell_two_bits_fc.add(gdstk.Label('r1', (21.41,16.615), layer=69, texttype=5))
arbiter_cell_two_bits_fc.add(gdstk.Label('r0', (22.062,33.077), layer=69, texttype=5))
arbiter_cell_two_bits_fc.add(gdstk.Label('rc', (17.037,21.732), layer=67, texttype=5))
arbiter_cell_two_bits_fc.add(gdstk.Label('g0', (20.455,33.615), layer=69, texttype=5))
arbiter_cell_two_bits_fc.add(gdstk.Label('g1', (18.075,13.96), layer=69, texttype=5))
arbiter_cell_two_bits_fc.add(gdstk.Label('gc', (16.3,24.575), layer=68, texttype=5))
arbiter_cell_two_bits_fc.add(gdstk.Label('VDD', (9.48,23.902), layer=69, texttype=5))
arbiter_cell_two_bits_fc.add(gdstk.Label('GND', (9.4,21.202), layer=68, texttype=5))

lib.write_gds('arbiter_cell_two_bits_fc.gds')
